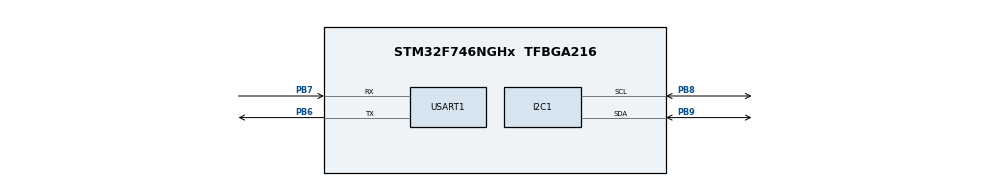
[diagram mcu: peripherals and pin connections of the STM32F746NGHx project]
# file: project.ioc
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CORTEX_M7.default_mode_Activation=1
I2C1.Timing=0x20404768
Mcu.Family=STM32F7
Mcu.Name=STM32F746NGHx
Mcu.Package=TFBGA216
NVIC.PriorityGroup=NVIC_PRIORITYGROUP_4
PB6.Mode=Asynchronous
PB6.Signal=USART1_TX
PB7.Mode=Asynchronous
PB7.Signal=USART1_RX
PB8.Mode=I2C
PB8.Signal=I2C1_SCL
PB9.Mode=I2C
PB9.Signal=I2C1_SDA
ProjectManager.HeapSize=0x200
ProjectManager.StackSize=0x400
ProjectManager.TargetToolchain=STM32CubeIDE
RCC.AHBFreq_Value=216000000
RCC.APB1CLKDivider=RCC_HCLK_DIV4
RCC.APB1Freq_Value=54000000
RCC.APB1TimFreq_Value=108000000
RCC.APB2CLKDivider=RCC_HCLK_DIV2
RCC.APB2Freq_Value=108000000
RCC.APB2TimFreq_Value=216000000
RCC.CortexFreq_Value=216000000
RCC.HCLKFreq_Value=216000000
RCC.HSE_VALUE=25000000
RCC.HSI_VALUE=16000000
RCC.LSE_VALUE=32768
RCC.PLLN=432
RCC.SYSCLKFreq_VALUE=216000000
RCC.SYSCLKSource=RCC_SYSCLKSOURCE_PLLCLK
RCC.USBFreq_Value=216000000
RCC.VCOOutputFreq_Value=432000000
USART1.VirtualMode-Asynchronous=VM_ASYNC
board=custom

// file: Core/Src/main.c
/* USER CODE BEGIN Header */
/**
  **************************
  * @file           : main.c
  * @brief          : Main program body
  **************************
  * @attention
  *
  * Copyright (c) 2025 STMicroelectronics.
  * All rights reserved.
  *
  * This software is licensed under terms that can be found in the LICENSE file
  * in the root directory of this software component.
  * If no LICENSE file comes with this software, it is provided AS-IS.
  *
  **************************
  */
/* USER CODE END Header */
#include "main.h"
#include "i2c.h"
#include "usart.h"
#include "gpio.h"

#include <stdio.h>
#include <string.h>
#include "sensors.h"
#include "BMP180_api.h"

bmp180_reading_t bmp_data;
th09c_reading_t th09c_data;

void SystemClock_Config(void);
static void MPU_Config(void);

/* USER CODE BEGIN 0 */
int __io_putchar(int ch) {
  HAL_UART_Transmit(&huart1, (uint8_t *)&ch, 1, HAL_MAX_DELAY);
  return ch;
}

/* USER CODE END 0 */

int main(void)
{

  /* MPU Configuration--------------------------------------------------------*/
  MPU_Config();

  /* MCU Configuration--------------------------------------------------------*/

  /* Reset of all peripherals, Initializes the Flash interface and the Systick. */
  HAL_Init();

  /* Configure the system clock */
  SystemClock_Config();

  /* Initialize all configured peripherals */
  MX_GPIO_Init();
  MX_I2C1_Init();
  MX_USART1_UART_Init();
  /* USER CODE BEGIN 2 */
  sensor_init(&hi2c1);
  /* USER CODE END 2 */

  /* Infinite loop */
  /* USER CODE BEGIN WHILE */
  while(1){
    // Read BMP180 sensor data
    bmp_data = sensor_read_bmp180(&hi2c1);

    // Check for errors in BMP180 reading
    if (bmp_data.status != HAL_OK)
    {
      printf("Error reading BMP180 sensor: status %d\r\n", bmp_data.status);
    }
    else
    {
      // Print BMP180 data over UART with 2 decimal places
      float temp = bmp_data.temperature / 100.0f;
      float pressure = bmp_data.pressure / 100.0f;  // Convert Pa to hPa

      printf("BMP180: Temp=%.2f°C, Pressure=%.2f hPa\r\n", temp, pressure);
    }

    // Read TH09C sensor data
    th09c_data = sensor_read_th09c(&hi2c1);

    // Check for errors in TH09C reading
    if (th09c_data.status != HAL_OK)
    {
      printf("Error reading TH09C sensor: status %d\r\n", th09c_data.status);
    }
    else
    {
      // Print TH09C data over UART with 2 decimal places
      printf("TH09C: Temp=%.2f°C, Humidity=%.2f%%\r\n",
             th09c_data.temperature, th09c_data.humidity);
    }

    // Delay between readings
    HAL_Delay(2000);  // 2 seconds between readings
  }
  /* USER CODE END 3 */
}

void SystemClock_Config(void)
{
  RCC_OscInitTypeDef RCC_OscInitStruct = {0};
  RCC_ClkInitTypeDef RCC_ClkInitStruct = {0};

  /** Configure the main internal regulator output voltage
  */
  __HAL_RCC_PWR_CLK_ENABLE();
  __HAL_PWR_VOLTAGESCALING_CONFIG(PWR_REGULATOR_VOLTAGE_SCALE1);

  /** Initializes the RCC Oscillators according to the specified parameters
  * in the RCC_OscInitTypeDef structure.
  */
  RCC_OscInitStruct.OscillatorType = RCC_OSCILLATORTYPE_HSE;
  RCC_OscInitStruct.HSEState = RCC_HSE_ON;
  RCC_OscInitStruct.PLL.PLLState = RCC_PLL_ON;
  RCC_OscInitStruct.PLL.PLLSource = RCC_PLLSOURCE_HSE;
  RCC_OscInitStruct.PLL.PLLM = 4;
  RCC_OscInitStruct.PLL.PLLN = 216;
  RCC_OscInitStruct.PLL.PLLP = RCC_PLLP_DIV2;
  RCC_OscInitStruct.PLL.PLLQ = 2;
  if (HAL_RCC_OscConfig(&RCC_OscInitStruct) != HAL_OK)
  {
    Error_Handler();
  }

  /** Activate the Over-Drive mode
  */
  if (HAL_PWREx_EnableOverDrive() != HAL_OK)
  {
    Error_Handler();
  }

  /** Initializes the CPU, AHB and APB buses clocks
  */
  RCC_ClkInitStruct.ClockType = RCC_CLOCKTYPE_HCLK|RCC_CLOCKTYPE_SYSCLK
                              |RCC_CLOCKTYPE_PCLK1|RCC_CLOCKTYPE_PCLK2;
  RCC_ClkInitStruct.SYSCLKSource = RCC_SYSCLKSOURCE_PLLCLK;
  RCC_ClkInitStruct.AHBCLKDivider = RCC_SYSCLK_DIV1;
  RCC_ClkInitStruct.APB1CLKDivider = RCC_HCLK_DIV4;
  RCC_ClkInitStruct.APB2CLKDivider = RCC_HCLK_DIV2;

  if (HAL_RCC_ClockConfig(&RCC_ClkInitStruct, FLASH_LATENCY_7) != HAL_OK)
  {
    Error_Handler();
  }
}

 /* MPU Configuration */

void MPU_Config(void)
{
  MPU_Region_InitTypeDef MPU_InitStruct = {0};

  /* Disables the MPU */
  HAL_MPU_Disable();

  /** Initializes and configures the Region and the memory to be protected
  */
  MPU_InitStruct.Enable = MPU_REGION_ENABLE;
  MPU_InitStruct.Number = MPU_REGION_NUMBER0;
  MPU_InitStruct.BaseAddress = 0x0;
  MPU_InitStruct.Size = MPU_REGION_SIZE_4GB;
  MPU_InitStruct.SubRegionDisable = 0x87;
  MPU_InitStruct.TypeExtField = MPU_TEX_LEVEL0;
  MPU_InitStruct.AccessPermission = MPU_REGION_NO_ACCESS;
  MPU_InitStruct.DisableExec = MPU_INSTRUCTION_ACCESS_DISABLE;
  MPU_InitStruct.IsShareable = MPU_ACCESS_SHAREABLE;
  MPU_InitStruct.IsCacheable = MPU_ACCESS_NOT_CACHEABLE;
  MPU_InitStruct.IsBufferable = MPU_ACCESS_NOT_BUFFERABLE;

  HAL_MPU_ConfigRegion(&MPU_InitStruct);
  /* Enables the MPU */
  HAL_MPU_Enable(MPU_PRIVILEGED_DEFAULT);

}

void Error_Handler(void)
{
  __disable_irq();
  while (1)
  {
  }
}
